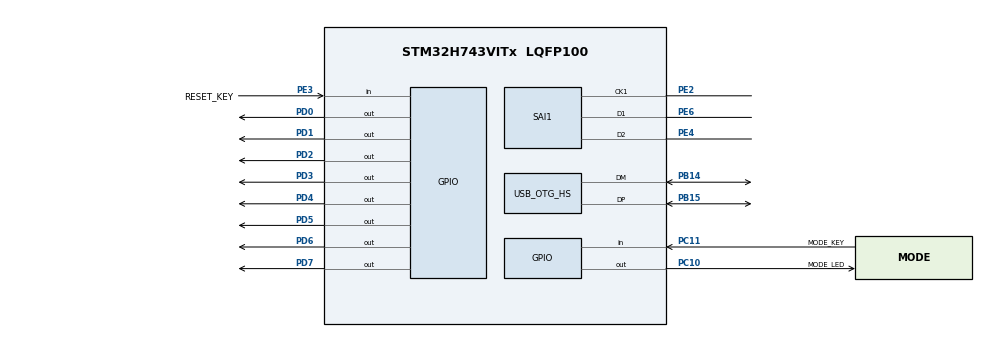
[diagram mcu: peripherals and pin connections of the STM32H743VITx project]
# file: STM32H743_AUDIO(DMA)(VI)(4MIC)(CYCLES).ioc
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CORTEX_M7.BaseAddress-Cortex_Memory_Protection_Unit_Region0_Settings=0x30000000
CORTEX_M7.CPU_DCache=Disabled
CORTEX_M7.CPU_ICache=Enabled
CORTEX_M7.Enable-Cortex_Memory_Protection_Unit_Region0_Settings=MPU_REGION_ENABLE
CORTEX_M7.IsCacheable-Cortex_Memory_Protection_Unit_Region0_Settings=MPU_ACCESS_CACHEABLE
CORTEX_M7.IsShareable-Cortex_Memory_Protection_Unit_Region0_Settings=MPU_ACCESS_SHAREABLE
CORTEX_M7.MPU_Control=MPU_HFNMI_PRIVDEF
CORTEX_M7.Size-Cortex_Memory_Protection_Unit_Region0_Settings=MPU_REGION_SIZE_128KB
Dma.Request0=SAI1_A
Dma.SAI1_A.0.Direction=DMA_PERIPH_TO_MEMORY
Dma.SAI1_A.0.EventEnable=DISABLE
Dma.SAI1_A.0.FIFOMode=DMA_FIFOMODE_DISABLE
Dma.SAI1_A.0.Instance=DMA1_Stream0
Dma.SAI1_A.0.MemDataAlignment=DMA_MDATAALIGN_HALFWORD
Dma.SAI1_A.0.MemInc=DMA_MINC_ENABLE
Dma.SAI1_A.0.Mode=DMA_CIRCULAR
Dma.SAI1_A.0.PeriphDataAlignment=DMA_PDATAALIGN_HALFWORD
Dma.SAI1_A.0.PeriphInc=DMA_PINC_DISABLE
Dma.SAI1_A.0.Polarity=HAL_DMAMUX_REQ_GEN_RISING
Dma.SAI1_A.0.Priority=DMA_PRIORITY_LOW
Dma.SAI1_A.0.RequestNumber=1
Dma.SAI1_A.0.SignalID=NONE
Dma.SAI1_A.0.SyncEnable=DISABLE
Dma.SAI1_A.0.SyncPolarity=HAL_DMAMUX_SYNC_NO_EVENT
Dma.SAI1_A.0.SyncRequestNumber=1
Dma.SAI1_A.0.SyncSignalID=NONE
Mcu.Family=STM32H7
Mcu.Name=STM32H743VITx
Mcu.Package=LQFP100
NVIC.DMA1_Stream0_IRQn=true\:2\:0\:true\:false\:true\:false\:true
NVIC.OTG_HS_IRQn=true\:3\:0\:true\:false\:true\:false\:true
NVIC.PriorityGroup=NVIC_PRIORITYGROUP_4
PB14.Mode=Device_Only_FS
PB14.Signal=USB_OTG_HS_DM
PB15.Mode=Device_Only_FS
PB15.Signal=USB_OTG_HS_DP
PC10.GPIO_Label=MODE_LED
PC10.Signal=GPIO_Output
PC11.GPIO_Label=MODE_KEY
PC11.GPIO_PuPd=GPIO_PULLDOWN
PC11.Signal=GPIO_Input
PD0.Signal=GPIO_Output
PD1.Signal=GPIO_Output
PD2.Signal=GPIO_Output
PD3.Signal=GPIO_Output
PD4.Signal=GPIO_Output
PD5.Signal=GPIO_Output
PD6.Signal=GPIO_Output
PD7.Signal=GPIO_Output
PDM2PCM.CHANNEL1_decimation_factor=PDM_FILTER_DEC_FACTOR_32
PDM2PCM.CHANNEL1_in_ptr_channels=2
PDM2PCM.CHANNEL1_mic_gain=5
PDM2PCM.CHANNEL1_out_ptr_channels=2
PDM2PCM.CHANNEL1_output_samples_number=96
PDM2PCM.CHANNEL2_in_ptr_channels=4
PE2.Mode=PDM_Master_Mode_CK1
PE2.Signal=SAI1_CK1
PE3.GPIO_Label=RESET_KEY
PE3.GPIO_PuPd=GPIO_PULLUP
PE3.Signal=GPIO_Input
PE4.Mode=3_4_MicroPhones
PE4.Signal=SAI1_D2
PE6.Mode=PDM_Master_Mode_CK1
PE6.Signal=SAI1_D1
PH0-OSC_IN\ (PH0).Mode=HSE-External-Oscillator
PH0-OSC_IN\ (PH0).Signal=RCC_OSC_IN
PH1-OSC_OUT\ (PH1).Mode=HSE-External-Oscillator
PH1-OSC_OUT\ (PH1).Signal=RCC_OSC_OUT
ProjectManager.HeapSize=0x400
ProjectManager.StackSize=0x400
ProjectManager.TargetToolchain=MDK-ARM V5
RCC.ADCFreq_Value=6144000
RCC.APB1Freq_Value=59904000
RCC.APB2Freq_Value=59904000
RCC.APB3Freq_Value=59904000
RCC.APB4Freq_Value=59904000
RCC.CortexFreq_Value=239616000
RCC.D1CPRE=RCC_SYSCLK_DIV2
RCC.D1PPRE=RCC_APB3_DIV2
RCC.D2PPRE1=RCC_APB1_DIV2
RCC.D2PPRE2=RCC_APB2_DIV2
RCC.D3PPRE=RCC_APB4_DIV2
RCC.DIVM1=8
RCC.DIVM2=24
RCC.DIVM3=16
RCC.DIVN1=312
RCC.DIVN2=192
RCC.DIVN3=125
RCC.DIVP2=32
RCC.DIVP3=4
RCC.DIVQ1=20
RCC.DIVQ3=4
RCC.EnbaleCSS=true
RCC.HCLKFreq_Value=119808000
RCC.HPRE=RCC_HCLK_DIV2
RCC.HSE_VALUE=24576000
RCC.PLL2FRACN=0
RCC.PLLFRACN=0
RCC.SAI1CLockSelection=RCC_SAI1CLKSOURCE_PLL2
RCC.SYSCLKFreq_VALUE=479232000
RCC.SYSCLKSource=RCC_SYSCLKSOURCE_PLLCLK
RCC.USBCLockSelection=RCC_USBCLKSOURCE_PLL3
RCC.USBFreq_Value=48000000
SAI1.Activation=ENABLE
SAI1.DataSize-PDM_Master_Mode_CK1=SAI_DATASIZE_16
SAI1.ErrorAudioFreq-PDM_Master_Mode_CK1=-87.5 %
SAI1.FSPolarity-PDM_Master_Mode_CK1=SAI_FS_ACTIVE_HIGH
SAI1.FirstBit-PDM_Master_Mode_CK1=SAI_FIRSTBIT_LSB
SAI1.FrameLength-PDM_Master_Mode_CK1=32
SAI1.Instance-PDM_Master_Mode_CK1=SAI$Index_Block_A
SAI1.MClockEnable=SAI_MASTERCLOCK_DISABLE
SAI1.NoDivider-PDM_Master_Mode_CK1=SAI_MASTERDIVIDER_DISABLE
SAI1.RealAudioFreq-PDM_Master_Mode_CK1=192.0 KHz
SAI1.SlotActive-PDM_Master_Mode_CK1=0x0000FFFF
SAI1.SlotNumber-PDM_Master_Mode_CK1=2
SAI1.VirtualMode-PDM_Master_Mode_CK1=VM_MASTER
SAI1.VirtualProtocol-PDM_Master_Mode_CK1=VM_PDM_PROTOCOL
SAI1.VirtualSlotActive-PDM_Master_Mode_CK1=SAI_SLOTACTIVE_ALL
USB_DEVICE.CLASS_NAME_HS=AUDIO
USB_DEVICE.USBD_MAX_NUM_INTERFACES-AUDIO_HS=2
USB_DEVICE.USBD_SELF_POWERED-AUDIO_HS=0
USB_DEVICE.VirtualMode-AUDIO_HS=Audio
USB_DEVICE.VirtualModeHS=Audio_HS
USB_OTG_HS.Sof_enable-Device_Only_FS=ENABLE
USB_OTG_HS.VirtualMode-Device_Only_FS=Device_Only_FS
VP_CRC_VS_CRC.Mode=CRC_Activate
VP_PDM2PCM_VS_PDM2PCM.Mode=PDM2PCM_Channel
VP_USB_DEVICE_VS_USB_DEVICE_AUDIO_HS.Mode=AUDIO_HS
board=custom

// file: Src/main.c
/* USER CODE BEGIN Header */
/**
  ******************************************************************************
  * @file           : main.c
  * @brief          : Main program body
  ******************************************************************************
  * @attention
  *
  * <h2><center>&copy; Copyright (c) 2020 STMicroelectronics.
  * All rights reserved.</center></h2>
  *
  * This software component is licensed by ST under Ultimate Liberty license
  * SLA0044, the "License"; You may not use this file except in compliance with
  * the License. You may obtain a copy of the License at:
  *                             www.st.com/SLA0044
  *
  ******************************************************************************
  */
/* USER CODE END Header */

#include "main.h"
#include "pdm2pcm.h"
#include "usbd_audio.h"
#include "usb_device.h"

CRC_HandleTypeDef hcrc;

SAI_HandleTypeDef hsai_BlockA1;
DMA_HandleTypeDef hdma_sai1_a;

/* USER CODE BEGIN PV */
volatile uint8_t mic_num;

volatile uint8_t record_en;
volatile uint8_t in_mute;
volatile uint16_t in_volumn;
volatile uint32_t in_freq;
volatile uint8_t in_play_en;

volatile uint16_t in_rd_ptr;
volatile uint16_t in_wr_ptr;
volatile uint8_t in_choose;
volatile uint16_t in_remain_len;
volatile uint8_t collect_xfrc;
uint32_t DataInbuffer[AUDIO_IN_BUF_WORD];//total buffer
uint32_t PDMDatabufferX[PDM_IN_PACKET / 2];//PDM buffer
uint16_t xin_remain_len;

#ifdef ADAPTION_ENABLE
uint32_t DataInbufferP[AUDIO_IN_4MIC_PACKET / 4 + AUDIO_IN_4MIC_PACKET / 16];//Packet buffer
#else
uint32_t DataInbufferP[AUDIO_IN_4MIC_PACKET / 4];
#endif

volatile uint8_t firstin_xfrc;

uint8_t state_in_full;
uint8_t state_in_empty;
uint8_t state_in_freq;
uint8_t state_in_dmae;
uint8_t state_in_flhin;
uint8_t state_in_trans;
uint16_t state_in_upadj;
uint16_t state_in_dnadj;

uint16_t in_count = 0;
uint16_t sof_count= 0;
uint16_t sai_countl = 0;
uint16_t sai_counth = 0;

uint16_t xin_count;
uint16_t xsof_count;
uint16_t xsai_countl = 0;
uint16_t xsai_counth = 0;

#ifdef MYDEBUG
uint16_t xcount;
uint32_t freq[64];
uint32_t time[64];
uint8_t  type[64];
uint32_t in_max_real;
uint32_t in_min_real;
#endif
/* USER CODE END PV */

void SystemClock_Config(void);
static void MPU_Config(void);
static void MX_GPIO_Init(void);
static void MX_DMA_Init(void);
static void MX_CRC_Init(void);
static void MX_SAI1_Init(void);

/* USER CODE BEGIN 0 */
void HAL_SAI_RxHalfCpltCallback(SAI_HandleTypeDef *hsai)
{
	if(hsai->Instance == SAI1_Block_A)
	{
		sai_countl++;
		in_choose = 0x00;
		collect_xfrc = 0x01;
	}
}

void HAL_SAI_RxCpltCallback(SAI_HandleTypeDef *hsai)
{
	if(hsai->Instance == SAI1_Block_A)
	{
		sai_counth++;
		in_choose = 0x01;
		collect_xfrc = 0x01;
	}
}

void MIC_Number_Init()
{
	if(GPIO_PIN_RESET == HAL_GPIO_ReadPin(GPIOC, GPIO_PIN_11))
	{
		mic_num = 2;
		HAL_GPIO_WritePin(GPIOC, GPIO_PIN_10, GPIO_PIN_RESET);
	}
	else
	{
		mic_num = 4;
		HAL_GPIO_WritePin(GPIOC, GPIO_PIN_10, GPIO_PIN_SET);
	}
}
/* USER CODE END 0 */

int main(void)
{
  /* USER CODE BEGIN 1 */

	uint16_t* PDMDatabuffer0;
	uint16_t* PDMDatabuffer1;
  /* USER CODE END 1 */

  /* MPU Configuration--------------------------------------------------------*/
  MPU_Config();

  /* Enable I-Cache---------------------------------------------------------*/
  SCB_EnableICache();

  /* Enable D-Cache---------------------------------------------------------*/
//  SCB_EnableDCache();

  /* MCU Configuration--------------------------------------------------------*/

  /* Reset of all peripherals, Initializes the Flash interface and the Systick. */
  HAL_Init();

  /* USER CODE BEGIN Init */
  MX_GPIO_Init();
	MIC_Number_Init();
  /* USER CODE END Init */

  /* Configure the system clock */
  SystemClock_Config();

  /* Initialize all configured peripherals */
  MX_DMA_Init();
  MX_CRC_Init();
  MX_SAI1_Init();
  MX_PDM2PCM_Init(mic_num);

	in_mute = 0;
	in_volumn = 0;
	record_en = 0x00;

	collect_xfrc = 0;
	firstin_xfrc = 0;

  /* USER CODE BEGIN 2 */
	state_in_full = 0;
	state_in_empty = 0;
	state_in_freq = 0;
	state_in_dmae = 0;
	state_in_flhin = 0;
	state_in_trans = 0;
	state_in_upadj = 0;
	state_in_dnadj = 0;

#ifdef MYDEBUG
	in_max_real = (uint16_t)(AUDIO_IN_BUF_WORD / 2);
	in_min_real = (uint16_t)(AUDIO_IN_BUF_WORD / 2);
#endif

  MX_USB_DEVICE_Init();
  /* USER CODE BEGIN 2 */

	PDMDatabuffer0 = (uint16_t *)(&PDMDatabufferX[0]);
	PDMDatabuffer1 = (uint16_t *)(&PDMDatabufferX[PDM_IN_PACKET / 4]);
  /* USER CODE END 2 */

  /* Infinite loop */
  while (1)
  {
#if 0
		in_count = 0;
		sof_count = 0;
		sai_countl = 0;
		sai_counth = 0;
		HAL_Delay(1000);
		xin_count = in_count;
		xsof_count = sof_count;
		xsai_countl = sai_countl;
		xsai_counth = sai_counth;
#endif
    /* USER CODE BEGIN 3 */

#if 1
		if(collect_xfrc == 1)//SAI COLLECT
		{
			collect_xfrc = 0;

			//PDM to PCM
			if(mic_num == 2)
			{
				if(in_choose == 0x00)
					PDM_To_PCM_2(PDMDatabuffer0, (uint16_t *)(&DataInbuffer[in_wr_ptr & (uint16_t)(AUDIO_IN_BUF_WORD - 1)]));
				else
					PDM_To_PCM_2(PDMDatabuffer1, (uint16_t *)(&DataInbuffer[in_wr_ptr & (uint16_t)(AUDIO_IN_BUF_WORD - 1)]));
			}
			else if(mic_num == 4)
			{
				if(in_choose == 0x00)
					PDM_To_PCM_4(PDMDatabuffer0, (uint16_t *)(&DataInbuffer[in_wr_ptr & (uint16_t)(AUDIO_IN_BUF_WORD - 1)]));
				else
					PDM_To_PCM_4(PDMDatabuffer1, (uint16_t *)(&DataInbuffer[in_wr_ptr & (uint16_t)(AUDIO_IN_BUF_WORD - 1)]));
			}

			//Update wr_ptr
			in_wr_ptr += (uint16_t)(PDM_IN_PACKET / 2 / 4);

			//Check Full
			if((uint16_t)(in_wr_ptr - in_rd_ptr) >= (uint16_t)(AUDIO_IN_BUF_WORD - AUDIO_IN_4MIC_PACKET / 4))//FULL
			{
				init_in_parameter();
#ifdef MYDEBUG
				time[xcount] = HAL_GetTick();
				type[xcount] = 0x01;
				xcount++;
				if(xcount == 64)
					xcount = 63;
#endif
				HAL_GPIO_WritePin(GPIOD, GPIO_PIN_0, GPIO_PIN_RESET);
				state_in_full++;
			}
		}
#endif
    /* USER CODE BEGIN 3 */
  }
  /* USER CODE END 3 */
}

void SystemClock_Config(void)
{
  RCC_OscInitTypeDef RCC_OscInitStruct = {0};
  RCC_ClkInitTypeDef RCC_ClkInitStruct = {0};
  RCC_PeriphCLKInitTypeDef PeriphClkInitStruct = {0};

  /** Supply configuration update enable
  */
  HAL_PWREx_ConfigSupply(PWR_LDO_SUPPLY);
  /** Configure the main internal regulator output voltage
  */
  __HAL_PWR_VOLTAGESCALING_CONFIG(PWR_REGULATOR_VOLTAGE_SCALE0);

  while(!__HAL_PWR_GET_FLAG(PWR_FLAG_VOSRDY)) {}
  /** Macro to configure the PLL clock source
  */
  __HAL_RCC_PLL_PLLSOURCE_CONFIG(RCC_PLLSOURCE_HSE);
  /** Initializes the CPU, AHB and APB busses clocks
  */
  RCC_OscInitStruct.OscillatorType = RCC_OSCILLATORTYPE_HSE;
  RCC_OscInitStruct.HSEState = RCC_HSE_ON;
  RCC_OscInitStruct.PLL.PLLState = RCC_PLL_ON;
  RCC_OscInitStruct.PLL.PLLSource = RCC_PLLSOURCE_HSE;
  RCC_OscInitStruct.PLL.PLLM = 8;
  RCC_OscInitStruct.PLL.PLLN = 312;
  RCC_OscInitStruct.PLL.PLLP = 2;///////////////////////////////
  RCC_OscInitStruct.PLL.PLLQ = 20;
  RCC_OscInitStruct.PLL.PLLR = 2;
  RCC_OscInitStruct.PLL.PLLRGE = RCC_PLL1VCIRANGE_1;
  RCC_OscInitStruct.PLL.PLLVCOSEL = RCC_PLL1VCOWIDE;
  RCC_OscInitStruct.PLL.PLLFRACN = 0;
  if (HAL_RCC_OscConfig(&RCC_OscInitStruct) != HAL_OK)
  {
    Error_Handler();
  }
  /** Initializes the CPU, AHB and APB busses clocks
  */
  RCC_ClkInitStruct.ClockType = RCC_CLOCKTYPE_HCLK|RCC_CLOCKTYPE_SYSCLK
                              |RCC_CLOCKTYPE_PCLK1|RCC_CLOCKTYPE_PCLK2
                              |RCC_CLOCKTYPE_D3PCLK1|RCC_CLOCKTYPE_D1PCLK1;
  RCC_ClkInitStruct.SYSCLKSource = RCC_SYSCLKSOURCE_PLLCLK;
  RCC_ClkInitStruct.SYSCLKDivider = RCC_SYSCLK_DIV1;
  RCC_ClkInitStruct.AHBCLKDivider = RCC_HCLK_DIV2;
  RCC_ClkInitStruct.APB3CLKDivider = RCC_APB3_DIV2;
  RCC_ClkInitStruct.APB1CLKDivider = RCC_APB1_DIV2;
  RCC_ClkInitStruct.APB2CLKDivider = RCC_APB2_DIV2;
  RCC_ClkInitStruct.APB4CLKDivider = RCC_APB4_DIV2;

  if (HAL_RCC_ClockConfig(&RCC_ClkInitStruct, FLASH_LATENCY_4) != HAL_OK)
  {
    Error_Handler();
  }
  PeriphClkInitStruct.PeriphClockSelection = RCC_PERIPHCLK_SAI1|RCC_PERIPHCLK_USB;
  PeriphClkInitStruct.PLL2.PLL2M = 24;
  PeriphClkInitStruct.PLL2.PLL2N = 192;
	if(mic_num == 2)
		PeriphClkInitStruct.PLL2.PLL2P = 32;
	if(mic_num == 4)
		PeriphClkInitStruct.PLL2.PLL2P = 16;
  PeriphClkInitStruct.PLL2.PLL2Q = 2;
  PeriphClkInitStruct.PLL2.PLL2R = 2;
  PeriphClkInitStruct.PLL2.PLL2RGE = RCC_PLL2VCIRANGE_0;
  PeriphClkInitStruct.PLL2.PLL2VCOSEL = RCC_PLL2VCOWIDE;
  PeriphClkInitStruct.PLL2.PLL2FRACN = 0;
  PeriphClkInitStruct.PLL3.PLL3M = 16;
  PeriphClkInitStruct.PLL3.PLL3N = 125;
  PeriphClkInitStruct.PLL3.PLL3P = 4;
  PeriphClkInitStruct.PLL3.PLL3Q = 4;
  PeriphClkInitStruct.PLL3.PLL3R = 2;
  PeriphClkInitStruct.PLL3.PLL3RGE = RCC_PLL3VCIRANGE_0;
  PeriphClkInitStruct.PLL3.PLL3VCOSEL = RCC_PLL3VCOWIDE;
  PeriphClkInitStruct.PLL3.PLL3FRACN = 0;
  PeriphClkInitStruct.Sai1ClockSelection = RCC_SAI1CLKSOURCE_PLL2;
  PeriphClkInitStruct.UsbClockSelection = RCC_USBCLKSOURCE_PLL3;
  if (HAL_RCCEx_PeriphCLKConfig(&PeriphClkInitStruct) != HAL_OK)
  {
    Error_Handler();
  }
  /** Enables the Clock Security System
  */
  HAL_RCC_EnableCSS();
  /** Enable USB Voltage detector
  */
  HAL_PWREx_EnableUSBVoltageDetector();
}

static void MX_CRC_Init(void)
{

  hcrc.Instance = CRC;
  hcrc.Init.DefaultPolynomialUse = DEFAULT_POLYNOMIAL_ENABLE;
  hcrc.Init.DefaultInitValueUse = DEFAULT_INIT_VALUE_ENABLE;
  hcrc.Init.InputDataInversionMode = CRC_INPUTDATA_INVERSION_NONE;
  hcrc.Init.OutputDataInversionMode = CRC_OUTPUTDATA_INVERSION_DISABLE;
  hcrc.InputDataFormat = CRC_INPUTDATA_FORMAT_BYTES;
  if (HAL_CRC_Init(&hcrc) != HAL_OK)
  {
    Error_Handler();
  }
  __HAL_CRC_DR_RESET(&hcrc);

}

static void MX_SAI1_Init(void)
{

  hsai_BlockA1.Instance = SAI1_Block_A;
  hsai_BlockA1.Init.Protocol = SAI_FREE_PROTOCOL;
  hsai_BlockA1.Init.AudioMode = SAI_MODEMASTER_RX;
  hsai_BlockA1.Init.FirstBit = SAI_FIRSTBIT_LSB;
  hsai_BlockA1.Init.ClockStrobing = SAI_CLOCKSTROBING_FALLINGEDGE;
  hsai_BlockA1.Init.Synchro = SAI_ASYNCHRONOUS;
  hsai_BlockA1.Init.OutputDrive = SAI_OUTPUTDRIVE_DISABLE;
  hsai_BlockA1.Init.NoDivider = SAI_MASTERDIVIDER_DISABLE;
  hsai_BlockA1.Init.FIFOThreshold = SAI_FIFOTHRESHOLD_EMPTY;
  hsai_BlockA1.Init.MonoStereoMode = SAI_STEREOMODE;
  hsai_BlockA1.Init.CompandingMode = SAI_NOCOMPANDING;
  hsai_BlockA1.Init.PdmInit.Activation = ENABLE;
  hsai_BlockA1.Init.PdmInit.ClockEnable = SAI_PDM_CLOCK1_ENABLE;
	if(mic_num == 2)
	{
		hsai_BlockA1.Init.PdmInit.MicPairsNbr = 1;
		hsai_BlockA1.FrameInit.FrameLength = 16;
		hsai_BlockA1.Init.DataSize = SAI_DATASIZE_16;
		hsai_BlockA1.SlotInit.SlotNumber = 1;
	}
	else if(mic_num == 4)
	{
		hsai_BlockA1.Init.PdmInit.MicPairsNbr = 2;
		hsai_BlockA1.FrameInit.FrameLength = 32;
		hsai_BlockA1.Init.DataSize = SAI_DATASIZE_16;
		hsai_BlockA1.SlotInit.SlotNumber = 2;
	}
	hsai_BlockA1.FrameInit.ActiveFrameLength = 1;
  hsai_BlockA1.FrameInit.FSDefinition = SAI_FS_STARTFRAME;
  hsai_BlockA1.FrameInit.FSPolarity = SAI_FS_ACTIVE_HIGH;
  hsai_BlockA1.FrameInit.FSOffset = SAI_FS_FIRSTBIT;
  hsai_BlockA1.SlotInit.FirstBitOffset = 0;
  hsai_BlockA1.SlotInit.SlotSize = SAI_SLOTSIZE_DATASIZE;
  hsai_BlockA1.SlotInit.SlotActive = 0x0000FFFF;

  if (HAL_SAI_Init(&hsai_BlockA1) != HAL_OK)
  {
    Error_Handler();
  }

}

static void MX_DMA_Init(void)
{

  /* DMA controller clock enable */
  __HAL_RCC_DMA1_CLK_ENABLE();

  /* DMA interrupt init */
  /* DMA1_Stream0_IRQn interrupt configuration */
  HAL_NVIC_SetPriority(DMA1_Stream0_IRQn, 2, 0);
  HAL_NVIC_EnableIRQ(DMA1_Stream0_IRQn);

}

static void MX_GPIO_Init(void)
{
  GPIO_InitTypeDef GPIO_InitStruct = {0};

  /* GPIO Ports Clock Enable */
  __HAL_RCC_GPIOA_CLK_ENABLE();
  __HAL_RCC_GPIOC_CLK_ENABLE();
  __HAL_RCC_GPIOD_CLK_ENABLE();
  __HAL_RCC_GPIOE_CLK_ENABLE();
  __HAL_RCC_GPIOH_CLK_ENABLE();

	/*Configure GPIO pin : PE3 */
	GPIO_InitStruct.Pin = GPIO_PIN_3;//RESET KEY
  GPIO_InitStruct.Mode = GPIO_MODE_INPUT;
  GPIO_InitStruct.Pull = GPIO_PULLUP;
  GPIO_InitStruct.Speed = GPIO_SPEED_FREQ_LOW;
  HAL_GPIO_Init(GPIOE, &GPIO_InitStruct);

  /*Configure GPIO pin : PC11 */
	GPIO_InitStruct.Pin = GPIO_PIN_11;//MODE KEY
  GPIO_InitStruct.Mode = GPIO_MODE_INPUT;
  GPIO_InitStruct.Pull = GPIO_PULLDOWN;
  GPIO_InitStruct.Speed = GPIO_SPEED_FREQ_LOW;
  HAL_GPIO_Init(GPIOC, &GPIO_InitStruct);

  /*Configure GPIO pin Output Level */
  HAL_GPIO_WritePin(GPIOC, GPIO_PIN_10, GPIO_PIN_SET);

  /*Configure GPIO pins : PC10 */
  GPIO_InitStruct.Pin = GPIO_PIN_10;//MODE LED
  GPIO_InitStruct.Mode = GPIO_MODE_OUTPUT_PP;
  GPIO_InitStruct.Pull = GPIO_NOPULL;
  GPIO_InitStruct.Speed = GPIO_SPEED_FREQ_LOW;
  HAL_GPIO_Init(GPIOC, &GPIO_InitStruct);
}

/* MPU Configuration */

void MPU_Config(void)
{
  MPU_Region_InitTypeDef MPU_InitStruct = {0};

  /* Disables the MPU */
  HAL_MPU_Disable();
  /** Initializes and configures the Region and the memory to be protected
  */
  MPU_InitStruct.Enable = MPU_REGION_ENABLE;
  MPU_InitStruct.Number = MPU_REGION_NUMBER0;
  MPU_InitStruct.BaseAddress = 0x30000000;
  MPU_InitStruct.Size = MPU_REGION_SIZE_128KB;
  MPU_InitStruct.SubRegionDisable = 0x0;
  MPU_InitStruct.TypeExtField = MPU_TEX_LEVEL0;
  MPU_InitStruct.AccessPermission = MPU_REGION_NO_ACCESS;
  MPU_InitStruct.DisableExec = MPU_INSTRUCTION_ACCESS_ENABLE;
  MPU_InitStruct.IsShareable = MPU_ACCESS_SHAREABLE;
  MPU_InitStruct.IsCacheable = MPU_ACCESS_CACHEABLE;
  MPU_InitStruct.IsBufferable = MPU_ACCESS_NOT_BUFFERABLE;

  HAL_MPU_ConfigRegion(&MPU_InitStruct);
  /* Enables the MPU */
  HAL_MPU_Enable(MPU_HFNMI_PRIVDEF);

}

void Error_Handler(void)
{
}

/************************ (C) COPYRIGHT STMicroelectronics *****END OF FILE****/
